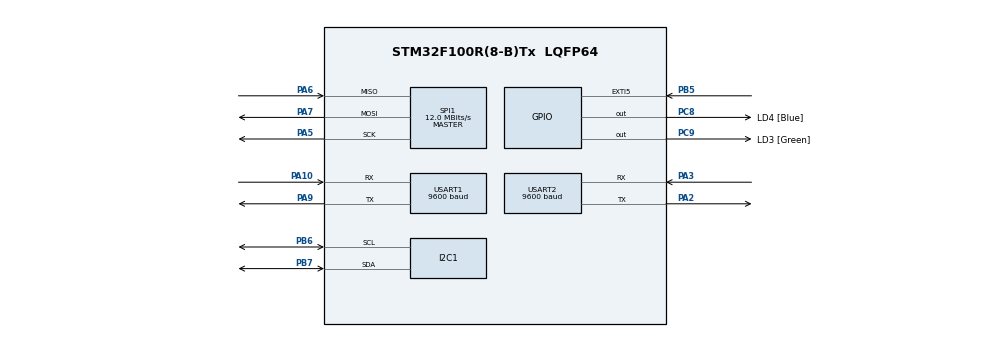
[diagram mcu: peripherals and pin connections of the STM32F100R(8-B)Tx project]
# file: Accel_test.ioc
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Mcu.Family=STM32F1
Mcu.Name=STM32F100R(8-B)Tx
Mcu.Package=LQFP64
NVIC.EXTI9_5_IRQn=true\:0\:0\:false\:false\:true\:true
NVIC.PriorityGroup=NVIC_PRIORITYGROUP_4
NVIC.USART1_IRQn=true\:1\:0\:true\:false\:true\:true
NVIC.USART2_IRQn=true\:1\:0\:true\:false\:true\:true
PA0-WKUP.Mode=SYS_WakeUp0
PA0-WKUP.Signal=SYS_WKUP
PA10.Mode=Asynchronous
PA10.Signal=USART1_RX
PA13.GPIO_Label=TMS_SWDIO
PA13.Mode=Serial_Wire
PA13.Signal=SYS_JTMS-SWDIO
PA14.GPIO_Label=TCK_SWCLK
PA14.Mode=Serial_Wire
PA14.Signal=SYS_JTCK-SWCLK
PA2.Mode=Asynchronous
PA2.Signal=USART2_TX
PA3.Mode=Asynchronous
PA3.Signal=USART2_RX
PA5.Mode=Full_Duplex_Master
PA5.Signal=SPI1_SCK
PA6.Mode=Full_Duplex_Master
PA6.Signal=SPI1_MISO
PA7.Mode=Full_Duplex_Master
PA7.Signal=SPI1_MOSI
PA9.Mode=Asynchronous
PA9.Signal=USART1_TX
PB5.Signal=GPXTI5
PB6.Mode=I2C
PB6.Signal=I2C1_SCL
PB7.Mode=I2C
PB7.Signal=I2C1_SDA
PC14-OSC32_IN.Mode=LSE-External-Oscillator
PC14-OSC32_IN.Signal=RCC_OSC32_IN
PC15-OSC32_OUT.Mode=LSE-External-Oscillator
PC15-OSC32_OUT.Signal=RCC_OSC32_OUT
PC8.GPIO_Label=LD4 [Blue]
PC8.Signal=GPIO_Output
PC9.GPIO_Label=LD3 [Green]
PC9.Signal=GPIO_Output
PD0-OSC_IN.Mode=HSE-External-Oscillator
PD0-OSC_IN.Signal=RCC_OSC_IN
PD1-OSC_OUT.Mode=HSE-External-Oscillator
PD1-OSC_OUT.Signal=RCC_OSC_OUT
ProjectManager.HeapSize=0x200
ProjectManager.StackSize=0x400
ProjectManager.TargetToolchain=MDK-ARM V5
RCC.AHBFreq_Value=24000000
RCC.APB1Freq_Value=24000000
RCC.APB1TimFreq_Value=24000000
RCC.APB2Freq_Value=24000000
RCC.APB2TimFreq_Value=24000000
RCC.HCLKFreq_Value=24000000
RCC.PLLMUL=RCC_PLL_MUL3
RCC.PLLSource=RCC_PLLSOURCE_HSE
RCC.SYSCLKFreq_VALUE=24000000
RCC.SYSCLKSource=RCC_SYSCLKSOURCE_PLLCLK
SPI1.CalculateBaudRate=12.0 MBits/s
SPI1.Direction=SPI_DIRECTION_2LINES
SPI1.Mode=SPI_MODE_MASTER
SPI1.VirtualType=VM_MASTER
USART1.BaudRate=9600
USART1.VirtualMode=VM_ASYNC
USART2.BaudRate=9600
USART2.VirtualMode=VM_ASYNC
board=STM32VLDISCOVERY

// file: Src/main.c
/* USER CODE BEGIN Header */
/**
  ******************************************************************************
  * @file           : main.c
  * @brief          : Main program body
  ******************************************************************************
  ** This notice applies to any and all portions of this file
  * that are not between comment pairs USER CODE BEGIN and
  * USER CODE END. Other portions of this file, whether
  * inserted by the user or by software development tools
  * are owned by their respective copyright owners.
  *
  * COPYRIGHT(c) 2019 STMicroelectronics
  *
  * Redistribution and use in source and binary forms, with or without modification,
  * are permitted provided that the following conditions are met:
  *   1. Redistributions of source code must retain the above copyright notice,
  *      this list of conditions and the following disclaimer.
  *   2. Redistributions in binary form must reproduce the above copyright notice,
  *      this list of conditions and the following disclaimer in the documentation
  *      and/or other materials provided with the distribution.
  *   3. Neither the name of STMicroelectronics nor the names of its contributors
  *      may be used to endorse or promote products derived from this software
  *      without specific prior written permission.
  *
  * THIS SOFTWARE IS PROVIDED BY THE COPYRIGHT HOLDERS AND CONTRIBUTORS "AS IS"
  * AND ANY EXPRESS OR IMPLIED WARRANTIES, INCLUDING, BUT NOT LIMITED TO, THE
  * IMPLIED WARRANTIES OF MERCHANTABILITY AND FITNESS FOR A PARTICULAR PURPOSE ARE
  * DISCLAIMED. IN NO EVENT SHALL THE COPYRIGHT HOLDER OR CONTRIBUTORS BE LIABLE
  * FOR ANY DIRECT, INDIRECT, INCIDENTAL, SPECIAL, EXEMPLARY, OR CONSEQUENTIAL
  * DAMAGES (INCLUDING, BUT NOT LIMITED TO, PROCUREMENT OF SUBSTITUTE GOODS OR
  * SERVICES; LOSS OF USE, DATA, OR PROFITS; OR BUSINESS INTERRUPTION) HOWEVER
  * CAUSED AND ON ANY THEORY OF LIABILITY, WHETHER IN CONTRACT, STRICT LIABILITY,
  * OR TORT (INCLUDING NEGLIGENCE OR OTHERWISE) ARISING IN ANY WAY OUT OF THE USE
  * OF THIS SOFTWARE, EVEN IF ADVISED OF THE POSSIBILITY OF SUCH DAMAGE.
  *
  ******************************************************************************
  */
/* USER CODE END Header */

#include "main.h"

/* USER CODE BEGIN Includes */
#include <string.h>
#include "uart.h"
#include "accel_i2c.h"
#include <stdbool.h>
#include "MPU6050.h"
/* USER CODE END Includes */

I2C_HandleTypeDef hi2c1;
SPI_HandleTypeDef hspi1;
UART_HandleTypeDef huart1;
UART_HandleTypeDef huart2;

/* USER CODE BEGIN PV */
bool int_flag;
uint8_t accel_z_data[100];
uint8_t accel_index = 0;
int16_t tempData = 0;
/* USER CODE END PV */

void SystemClock_Config(void);
static void MX_GPIO_Init(void);
static void MX_USART1_UART_Init(void);
static void MX_USART2_UART_Init(void);
static void MX_SPI1_Init(void);
static void MX_I2C1_Init(void);

int main(void)
{

  /* MCU Configuration--------------------------------------------------------*/

  /* Reset of all peripherals, Initializes the Flash interface and the Systick. */
  HAL_Init();

  /* Configure the system clock */
  SystemClock_Config();

  /* Initialize all configured peripherals */
  MX_GPIO_Init();
  MX_USART1_UART_Init();
  MX_USART2_UART_Init();
  MX_SPI1_Init();
  MX_I2C1_Init();
  /* USER CODE BEGIN 2 */
	print_str("wassup \n\r");
	uint8_t x = MPU6050_Init(&hi2c1);
	calibration(&hi2c1);

  /* USER CODE END 2 */

  /* Infinite loop */
  /* USER CODE BEGIN WHILE */
while (1)
  {
        if(int_flag == true)
				{
					int_flag = false;
					tempData = getAccel(&hi2c1);
					accel_z_data[accel_index] = (tempData & 0xff00)>>8;
					accel_z_data[accel_index+1] = tempData & 0xff;
					accel_index = accel_index+2;
				}

				if(accel_index == 100)
				{
					  send_to_xbee_for_transmitting(accel_z_data);
						accel_index = 0;
				}

  }

}

void SystemClock_Config(void)
{
  RCC_OscInitTypeDef RCC_OscInitStruct = {0};
  RCC_ClkInitTypeDef RCC_ClkInitStruct = {0};

  /**Initializes the CPU, AHB and APB busses clocks
  */
  RCC_OscInitStruct.OscillatorType = RCC_OSCILLATORTYPE_HSE;
  RCC_OscInitStruct.HSEState = RCC_HSE_ON;
  RCC_OscInitStruct.HSEPredivValue = RCC_HSE_PREDIV_DIV2;
  RCC_OscInitStruct.PLL.PLLState = RCC_PLL_ON;
  RCC_OscInitStruct.PLL.PLLSource = RCC_PLLSOURCE_HSE;
  RCC_OscInitStruct.PLL.PLLMUL = RCC_PLL_MUL5;
  if (HAL_RCC_OscConfig(&RCC_OscInitStruct) != HAL_OK)
  {
    Error_Handler();
  }
  /**Initializes the CPU, AHB and APB busses clocks
  */
  RCC_ClkInitStruct.ClockType = RCC_CLOCKTYPE_HCLK|RCC_CLOCKTYPE_SYSCLK
                              |RCC_CLOCKTYPE_PCLK1|RCC_CLOCKTYPE_PCLK2;
  RCC_ClkInitStruct.SYSCLKSource = RCC_SYSCLKSOURCE_PLLCLK;
  RCC_ClkInitStruct.AHBCLKDivider = RCC_SYSCLK_DIV4;
  RCC_ClkInitStruct.APB1CLKDivider = RCC_HCLK_DIV1;
  RCC_ClkInitStruct.APB2CLKDivider = RCC_HCLK_DIV1;

  if (HAL_RCC_ClockConfig(&RCC_ClkInitStruct, FLASH_LATENCY_0) != HAL_OK)
  {
    Error_Handler();
  }
}

static void MX_I2C1_Init(void)
{

  hi2c1.Instance = I2C1;
  hi2c1.Init.ClockSpeed = 100000;
  hi2c1.Init.DutyCycle = I2C_DUTYCYCLE_2;
  hi2c1.Init.OwnAddress1 = 0;
  hi2c1.Init.AddressingMode = I2C_ADDRESSINGMODE_7BIT;
  hi2c1.Init.DualAddressMode = I2C_DUALADDRESS_DISABLE;
  hi2c1.Init.OwnAddress2 = 0;
  hi2c1.Init.GeneralCallMode = I2C_GENERALCALL_DISABLE;
  hi2c1.Init.NoStretchMode = I2C_NOSTRETCH_DISABLE;
  if (HAL_I2C_Init(&hi2c1) != HAL_OK)
  {
    Error_Handler();
  }

}

static void MX_SPI1_Init(void)
{

  /* SPI1 parameter configuration*/
  hspi1.Instance = SPI1;
  hspi1.Init.Mode = SPI_MODE_MASTER;
  hspi1.Init.Direction = SPI_DIRECTION_2LINES;
  hspi1.Init.DataSize = SPI_DATASIZE_8BIT;
  hspi1.Init.CLKPolarity = SPI_POLARITY_LOW;
  hspi1.Init.CLKPhase = SPI_PHASE_1EDGE;
  hspi1.Init.NSS = SPI_NSS_SOFT;
  hspi1.Init.BaudRatePrescaler = SPI_BAUDRATEPRESCALER_2;
  hspi1.Init.FirstBit = SPI_FIRSTBIT_MSB;
  hspi1.Init.TIMode = SPI_TIMODE_DISABLE;
  hspi1.Init.CRCCalculation = SPI_CRCCALCULATION_DISABLE;
  hspi1.Init.CRCPolynomial = 10;
  if (HAL_SPI_Init(&hspi1) != HAL_OK)
  {
    Error_Handler();
  }

}

static void MX_USART1_UART_Init(void)
{

  huart1.Instance = USART1;
  huart1.Init.BaudRate = 115200;
  huart1.Init.WordLength = UART_WORDLENGTH_8B;
  huart1.Init.StopBits = UART_STOPBITS_1;
  huart1.Init.Parity = UART_PARITY_NONE;
  huart1.Init.Mode = UART_MODE_TX_RX;
  huart1.Init.HwFlowCtl = UART_HWCONTROL_NONE;
  huart1.Init.OverSampling = UART_OVERSAMPLING_16;
  if (HAL_UART_Init(&huart1) != HAL_OK)
  {
    Error_Handler();
  }

}

static void MX_USART2_UART_Init(void)
{

  huart2.Instance = USART2;
  huart2.Init.BaudRate = 115200;
  huart2.Init.WordLength = UART_WORDLENGTH_8B;
  huart2.Init.StopBits = UART_STOPBITS_1;
  huart2.Init.Parity = UART_PARITY_NONE;
  huart2.Init.Mode = UART_MODE_TX_RX;
  huart2.Init.HwFlowCtl = UART_HWCONTROL_NONE;
  huart2.Init.OverSampling = UART_OVERSAMPLING_16;
  if (HAL_UART_Init(&huart2) != HAL_OK)
  {
    Error_Handler();
  }

}

static void MX_GPIO_Init(void)
{
  GPIO_InitTypeDef GPIO_InitStruct = {0};

  /* GPIO Ports Clock Enable */
  __HAL_RCC_GPIOC_CLK_ENABLE();
  __HAL_RCC_GPIOD_CLK_ENABLE();
  __HAL_RCC_GPIOA_CLK_ENABLE();
  __HAL_RCC_GPIOB_CLK_ENABLE();

  /*Configure GPIO pin Output Level */
  HAL_GPIO_WritePin(GPIOC, LD4_Pin|LD3_Pin, GPIO_PIN_RESET);

  /*Configure GPIO pins : LD4_Pin LD3_Pin */
  GPIO_InitStruct.Pin = LD4_Pin|LD3_Pin;
  GPIO_InitStruct.Mode = GPIO_MODE_OUTPUT_PP;
  GPIO_InitStruct.Pull = GPIO_NOPULL;
  GPIO_InitStruct.Speed = GPIO_SPEED_FREQ_LOW;
  HAL_GPIO_Init(GPIOC, &GPIO_InitStruct);

  /*Configure GPIO pin : PB5 */
  GPIO_InitStruct.Pin = GPIO_PIN_5;
  GPIO_InitStruct.Mode = GPIO_MODE_IT_RISING;
  GPIO_InitStruct.Pull = GPIO_NOPULL;
  HAL_GPIO_Init(GPIOB, &GPIO_InitStruct);

  /* EXTI interrupt init*/
  HAL_NVIC_SetPriority(EXTI9_5_IRQn, 0, 0);
  HAL_NVIC_EnableIRQ(EXTI9_5_IRQn);

}

void Error_Handler(void)
{
}

/************************ (C) COPYRIGHT STMicroelectronics *****END OF FILE****/
